One B-rep face of a CAD part: STEP entity #807.
In plain terms, the planar face has unit normal (1, 0, 0).
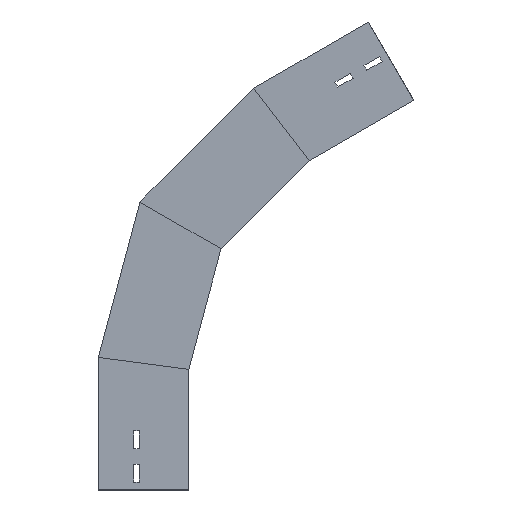
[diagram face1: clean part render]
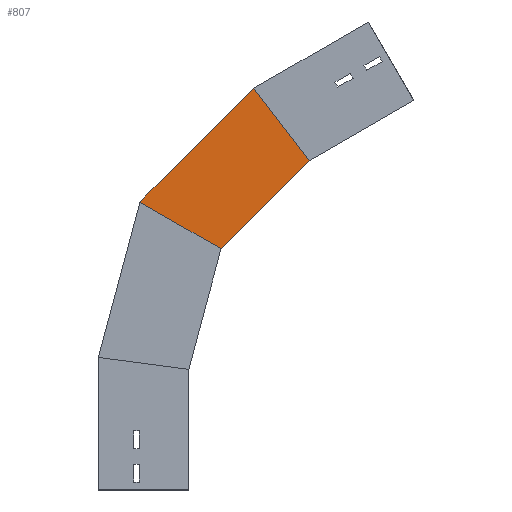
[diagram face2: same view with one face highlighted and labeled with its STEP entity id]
Its self-contained STEP definition (entity closure, numbers rounded to 3 decimals):
#6 = CARTESIAN_POINT ( 'NONE',  ( 0., -78.533, 277.539 ) ) ;
#29 = CARTESIAN_POINT ( 'NONE',  ( 0., 112.909, 163.284 ) ) ;
#45 = LINE ( 'NONE', #29, #944 ) ;
#93 = ORIENTED_EDGE ( 'NONE', *, *, #1083, .F. ) ;
#191 = CARTESIAN_POINT ( 'NONE',  ( 0., -40.117, 299.719 ) ) ;
#303 = VECTOR ( 'NONE', #730, 1000. ) ;
#310 = DIRECTION ( 'NONE',  ( 0., 0., -1. ) ) ;
#369 = CARTESIAN_POINT ( 'NONE',  ( 0., 0., 150. ) ) ;
#375 = ORIENTED_EDGE ( 'NONE', *, *, #1499, .T. ) ;
#398 = CARTESIAN_POINT ( 'NONE',  ( 0., -19.411, 147.444 ) ) ;
#465 = DIRECTION ( 'NONE',  ( 0., -0.259, 0.966 ) ) ;
#478 = AXIS2_PLACEMENT_3D ( 'NONE', #1344, #1196, #310 ) ;
#548 = LINE ( 'NONE', #6, #303 ) ;
#634 = ORIENTED_EDGE ( 'NONE', *, *, #772, .F. ) ;
#722 = VECTOR ( 'NONE', #465, 1000. ) ;
#730 = DIRECTION ( 'NONE',  ( 0., -0.866, -0.5 ) ) ;
#772 = EDGE_CURVE ( 'NONE', #1336, #1552, #1337, .T. ) ;
#788 = EDGE_LOOP ( 'NONE', ( #375, #1527, #634, #93 ) ) ;
#807 = ADVANCED_FACE ( 'NONE', ( #1189 ), #1068, .T. ) ;
#820 = CARTESIAN_POINT ( 'NONE',  ( 0., 112.5, 164.811 ) ) ;
#852 = DIRECTION ( 'NONE',  ( 0., -0.259, 0.966 ) ) ;
#944 = VECTOR ( 'NONE', #852, 1000. ) ;
#1043 = DIRECTION ( 'NONE',  ( 0., -0.991, -0.131 ) ) ;
#1068 = PLANE ( 'NONE',  #478 ) ;
#1083 = EDGE_CURVE ( 'NONE', #1594, #1336, #1545, .T. ) ;
#1087 = VERTEX_POINT ( 'NONE', #1154 ) ;
#1154 = CARTESIAN_POINT ( 'NONE',  ( 0., 60.748, 357.953 ) ) ;
#1189 = FACE_OUTER_BOUND ( 'NONE', #788, .T. ) ;
#1196 = DIRECTION ( 'NONE',  ( 1., 0., 0. ) ) ;
#1257 = VECTOR ( 'NONE', #1043, 1000. ) ;
#1336 = VERTEX_POINT ( 'NONE', #369 ) ;
#1337 = LINE ( 'NONE', #1588, #722 ) ;
#1344 = CARTESIAN_POINT ( 'NONE',  ( 0., 4.243, 134.167 ) ) ;
#1481 = EDGE_CURVE ( 'NONE', #1087, #1552, #548, .T. ) ;
#1499 = EDGE_CURVE ( 'NONE', #1594, #1087, #45, .T. ) ;
#1527 = ORIENTED_EDGE ( 'NONE', *, *, #1481, .T. ) ;
#1545 = LINE ( 'NONE', #398, #1257 ) ;
#1552 = VERTEX_POINT ( 'NONE', #191 ) ;
#1588 = CARTESIAN_POINT ( 'NONE',  ( 0., 4.243, 134.167 ) ) ;
#1594 = VERTEX_POINT ( 'NONE', #820 ) ;
